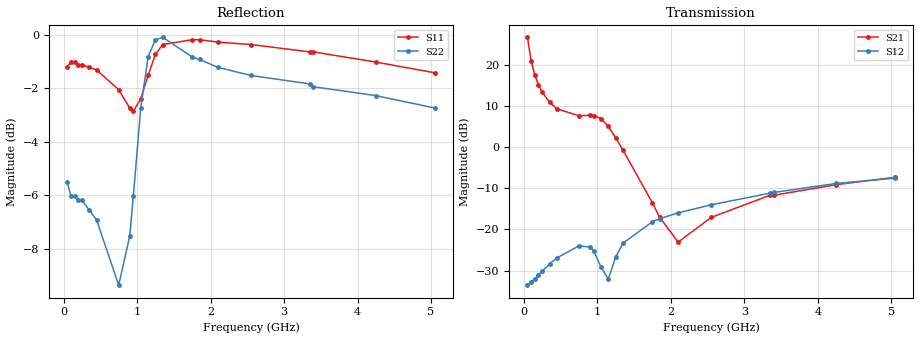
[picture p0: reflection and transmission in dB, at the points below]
!AT-33225
!S-PARAMETERS at Vce=3.6V  Ic=100mA.  LAST UPDATED 08-05-96
# ghz s ma r 50
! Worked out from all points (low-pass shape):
!   101 points, 50 MHz to 5.05 GHz, reference 50 ohm
!   highest |S21| = 26.70 dB at 50 MHz (marker M1); lowest = -23.1 dB at 2.1 GHz (marker M2)
!   |S21| within 3 dB of the highest: start of sweep to 75.99 MHz
!   lowest |S11| = -2.9 dB at 950 MHz (marker M3), VSWR 6.14, Z = 8.17 + j2.98 ohm
!   |S11| at or under -10 dB: nowhere
!   |S22| runs from -9.4 to -0.1 dB; largest |S21 - S12| = 22
!   S11 on the Smith chart (normalised r, x): 50 MHz: 0.07, -0.17; 450 MHz: 0.08, +0.05; 1.85 GHz: 0.01, +0.17; 3.35 GHz: 0.04, +0.36; 5.05 GHz: 0.11, +0.60
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0.05  0.87 -161.0  21.63 101.0  0.021 24.0  0.53 -145.0
0.1  0.89 -172.0  11.13 91.0  0.023 27.0  0.5 -163.0
0.15  0.89 -176.0  7.53 86.0  0.025 33.0  0.5 -170.0
0.2  0.88 -179.0  5.73 82.0  0.028 37.0  0.49 -173.0
0.25  0.88 179.0  4.68 78.0  0.031 41.0  0.49 -175.0
0.35  0.87 176.0  3.52 71.0  0.038 45.0  0.47 -178.0
0.45  0.86 174.0  2.93 64.0  0.045 47.0  0.45 -179.0
0.75  0.79 169.0  2.41 36.0  0.063 38.0  0.34 -164.0
0.9  0.73 171.0  2.44 13.0  0.061 26.0  0.42 -139.0
0.95  0.72 173.0  2.42 2.0  0.055 22.0  0.5 -134.0
1.05  0.76 179.0  2.23 -22.0  0.035 21.0  0.73 -138.0
1.15  0.84 180.0  1.79 -46.0  0.025 69.0  0.91 -150.0
1.25  0.92 177.0  1.3 -66.0  0.046 94.0  0.98 -161.0
1.35  0.96 174.0  0.92 -82.0  0.068 93.0  0.99 -171.0
1.75  0.98 163.0  0.21 -123.0  0.124 78.0  0.91 171.0
1.85  0.98 161.0  0.14 -136.0  0.135 76.0  0.9 168.0
2.1  0.97 157.0  0.07 154.0  0.159 70.0  0.87 162.0
2.55  0.96 151.0  0.14 80.0  0.199 62.0  0.84 153.0
3.35  0.93 140.0  0.26 54.0  0.276 50.0  0.81 138.0
3.4  0.93 140.0  0.26 53.0  0.281 49.0  0.8 137.0
4.25  0.89 128.0  0.35 35.0  0.362 33.0  0.77 117.0
5.05  0.85 118.0  0.43 18.0  0.42 18.0  0.73 95.0
